VERSION 5.7 ;
  NOWIREEXTENSIONATPIN ON ;
  DIVIDERCHAR "/" ;
  BUSBITCHARS "[]" ;
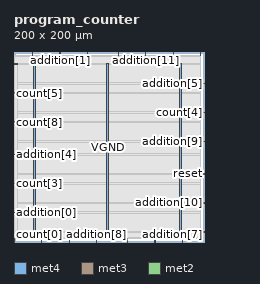
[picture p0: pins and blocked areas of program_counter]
MACRO program_counter
  CLASS BLOCK ;
  FOREIGN program_counter ;
  ORIGIN 0.000 0.000 ;
  SIZE 200.000 BY 200.000 ;
  PIN VGND
    USE GROUND ;
    PORT
      LAYER met4 ;
        RECT 97.840 10.640 99.440 187.920 ;
    END
  END VGND
  PIN VPWR
    USE POWER ;
    PORT
      LAYER met4 ;
        RECT 174.640 10.640 176.240 187.920 ;
    END
    PORT
      LAYER met4 ;
        RECT 21.040 10.640 22.640 187.920 ;
    END
  END VPWR
  PIN addition[0]
    PORT
      LAYER met3 ;
        RECT 0.000 30.640 4.000 31.240 ;
    END
  END addition[0]
  PIN addition[10]
    PORT
      LAYER met3 ;
        RECT 196.000 40.840 200.000 41.440 ;
    END
  END addition[10]
  PIN addition[11]
    PORT
      LAYER met2 ;
        RECT 138.550 196.000 138.830 200.000 ;
    END
  END addition[11]
  PIN addition[1]
    PORT
      LAYER met2 ;
        RECT 48.390 196.000 48.670 200.000 ;
    END
  END addition[1]
  PIN addition[2]
    PORT
      LAYER met3 ;
        RECT 0.000 187.040 4.000 187.640 ;
    END
  END addition[2]
  PIN addition[3]
    PORT
      LAYER met2 ;
        RECT 196.510 196.000 196.790 200.000 ;
    END
  END addition[3]
  PIN addition[4]
    PORT
      LAYER met3 ;
        RECT 0.000 91.840 4.000 92.440 ;
    END
  END addition[4]
  PIN addition[5]
    PORT
      LAYER met3 ;
        RECT 196.000 166.640 200.000 167.240 ;
    END
  END addition[5]
  PIN addition[6]
    PORT
      LAYER met2 ;
        RECT 167.530 196.000 167.810 200.000 ;
    END
  END addition[6]
  PIN addition[7]
    PORT
      LAYER met2 ;
        RECT 177.190 0.000 177.470 4.000 ;
    END
  END addition[7]
  PIN addition[8]
    PORT
      LAYER met2 ;
        RECT 87.030 0.000 87.310 4.000 ;
    END
  END addition[8]
  PIN addition[9]
    PORT
      LAYER met3 ;
        RECT 196.000 105.440 200.000 106.040 ;
    END
  END addition[9]
  PIN clk
    PORT
      LAYER met2 ;
        RECT 148.210 0.000 148.490 4.000 ;
    END
  END clk
  PIN count[0]
    PORT
      LAYER met2 ;
        RECT 0.090 0.000 0.370 4.000 ;
    END
  END count[0]
  PIN count[10]
    PORT
      LAYER met2 ;
        RECT 29.070 0.000 29.350 4.000 ;
    END
  END count[10]
  PIN count[11]
    PORT
      LAYER met2 ;
        RECT 77.370 196.000 77.650 200.000 ;
    END
  END count[11]
  PIN count[1]
    PORT
      LAYER met3 ;
        RECT 196.000 10.240 200.000 10.840 ;
    END
  END count[1]
  PIN count[2]
    PORT
      LAYER met2 ;
        RECT 58.050 0.000 58.330 4.000 ;
    END
  END count[2]
  PIN count[3]
    PORT
      LAYER met3 ;
        RECT 0.000 61.240 4.000 61.840 ;
    END
  END count[3]
  PIN count[4]
    PORT
      LAYER met3 ;
        RECT 196.000 136.040 200.000 136.640 ;
    END
  END count[4]
  PIN count[5]
    PORT
      LAYER met3 ;
        RECT 0.000 156.440 4.000 157.040 ;
    END
  END count[5]
  PIN count[6]
    PORT
      LAYER met2 ;
        RECT 109.570 196.000 109.850 200.000 ;
    END
  END count[6]
  PIN count[7]
    PORT
      LAYER met2 ;
        RECT 119.230 0.000 119.510 4.000 ;
    END
  END count[7]
  PIN count[8]
    PORT
      LAYER met3 ;
        RECT 0.000 125.840 4.000 126.440 ;
    END
  END count[8]
  PIN count[9]
    PORT
      LAYER met2 ;
        RECT 19.410 196.000 19.690 200.000 ;
    END
  END count[9]
  PIN reset
    PORT
      LAYER met3 ;
        RECT 196.000 71.440 200.000 72.040 ;
    END
  END reset
  OBS
      LAYER li1 ;
        RECT 5.520 10.795 194.120 187.765 ;
      LAYER met1 ;
        RECT 0.070 9.900 196.810 187.920 ;
      LAYER met2 ;
        RECT 0.100 195.720 19.130 196.000 ;
        RECT 19.970 195.720 48.110 196.000 ;
        RECT 48.950 195.720 77.090 196.000 ;
        RECT 77.930 195.720 109.290 196.000 ;
        RECT 110.130 195.720 138.270 196.000 ;
        RECT 139.110 195.720 167.250 196.000 ;
        RECT 168.090 195.720 196.230 196.000 ;
        RECT 0.100 4.280 196.780 195.720 ;
        RECT 0.650 4.000 28.790 4.280 ;
        RECT 29.630 4.000 57.770 4.280 ;
        RECT 58.610 4.000 86.750 4.280 ;
        RECT 87.590 4.000 118.950 4.280 ;
        RECT 119.790 4.000 147.930 4.280 ;
        RECT 148.770 4.000 176.910 4.280 ;
        RECT 177.750 4.000 196.780 4.280 ;
      LAYER met3 ;
        RECT 4.400 186.640 196.000 187.845 ;
        RECT 4.000 167.640 196.000 186.640 ;
        RECT 4.000 166.240 195.600 167.640 ;
        RECT 4.000 157.440 196.000 166.240 ;
        RECT 4.400 156.040 196.000 157.440 ;
        RECT 4.000 137.040 196.000 156.040 ;
        RECT 4.000 135.640 195.600 137.040 ;
        RECT 4.000 126.840 196.000 135.640 ;
        RECT 4.400 125.440 196.000 126.840 ;
        RECT 4.000 106.440 196.000 125.440 ;
        RECT 4.000 105.040 195.600 106.440 ;
        RECT 4.000 92.840 196.000 105.040 ;
        RECT 4.400 91.440 196.000 92.840 ;
        RECT 4.000 72.440 196.000 91.440 ;
        RECT 4.000 71.040 195.600 72.440 ;
        RECT 4.000 62.240 196.000 71.040 ;
        RECT 4.400 60.840 196.000 62.240 ;
        RECT 4.000 41.840 196.000 60.840 ;
        RECT 4.000 40.440 195.600 41.840 ;
        RECT 4.000 31.640 196.000 40.440 ;
        RECT 4.400 30.240 196.000 31.640 ;
        RECT 4.000 11.240 196.000 30.240 ;
        RECT 4.000 10.375 195.600 11.240 ;
  END
END program_counter
END LIBRARY

